###############################################################
#  Generated by:      Cadence Innovus 21.16-s078_1
#  OS:                Linux x86_64(Host ID micro03)
#  Generated on:      Mon Aug  3 20:32:39 2026
#  Design:            oadm_dm
#  Command:           write_lef_abstract oadm_dm.lef -5.7 -PgpinLayers 6 -specifyTopLayer 6 -stripePin
###############################################################

VERSION 5.7 ;

BUSBITCHARS "[]" ;
DIVIDERCHAR "/" ;

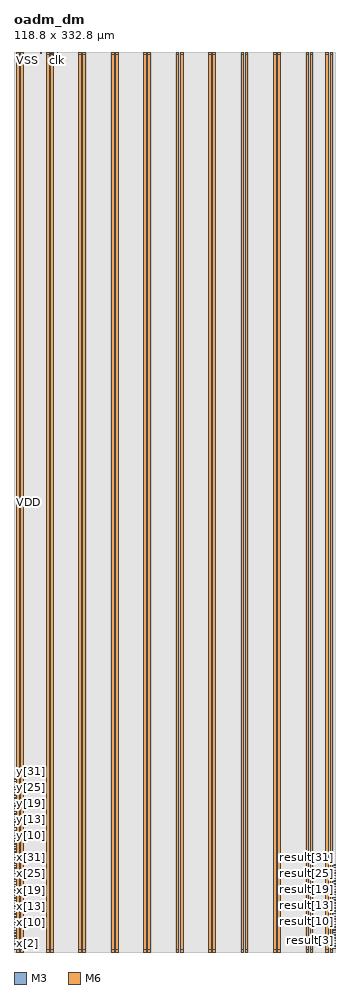
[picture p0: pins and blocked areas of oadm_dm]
MACRO oadm_dm
  CLASS BLOCK ;
  SIZE 118.800000 BY 332.800000 ;
  FOREIGN oadm_dm 0.000000 0.000000 ;
  ORIGIN 0 0 ;
  SYMMETRY X Y R90 ;
  PIN clk
    DIRECTION INPUT ;
    USE SIGNAL ;
    ANTENNAPARTIALMETALAREA 0.03 LAYER M3  ;
    ANTENNAPARTIALMETALSIDEAREA 0.132 LAYER M3  ;
    ANTENNAPARTIALCUTAREA 0.01 LAYER VIA3  ;
    ANTENNAPARTIALMETALAREA 0.898 LAYER M4  ;
    ANTENNAPARTIALMETALSIDEAREA 3.9952 LAYER M4  ;
    ANTENNAPARTIALCUTAREA 0.01 LAYER VIA4  ;
    ANTENNAPARTIALMETALAREA 0.958 LAYER M5  ;
    ANTENNAPARTIALMETALSIDEAREA 4.2592 LAYER M5  ;
    ANTENNAMODEL OXIDE1 ;
    ANTENNAGATEAREA 0.0996 LAYER M5  ;
    ANTENNAMAXAREACAR 11.7269 LAYER M5  ;
    ANTENNAMAXSIDEAREACAR 52.7149 LAYER M5  ;
    ANTENNAMAXCUTCAR 0.401606 LAYER VIA5  ;
    PORT
      LAYER M3 ;
        RECT 15.910000 332.200000 16.090000 332.800000 ;
    END
  END clk
  PIN x[31]
    DIRECTION INPUT ;
    USE SIGNAL ;
    ANTENNAPARTIALMETALAREA 0.579 LAYER M3  ;
    ANTENNAPARTIALMETALSIDEAREA 2.5476 LAYER M3  ;
    ANTENNAMODEL OXIDE1 ;
    ANTENNAGATEAREA 0.0273 LAYER M3  ;
    ANTENNAMAXAREACAR 28.2692 LAYER M3  ;
    ANTENNAMAXSIDEAREACAR 124.821 LAYER M3  ;
    ANTENNAMAXCUTCAR 0.732601 LAYER VIA3  ;
    PORT
      LAYER M3 ;
        RECT 0.000000 31.910000 0.600000 32.090000 ;
    END
  END x[31]
  PIN x[30]
    DIRECTION INPUT ;
    USE SIGNAL ;
    ANTENNAPARTIALMETALAREA 0.709 LAYER M3  ;
    ANTENNAPARTIALMETALSIDEAREA 3.1636 LAYER M3  ;
    ANTENNAMODEL OXIDE1 ;
    ANTENNAGATEAREA 0.0246 LAYER M3  ;
    ANTENNAMAXAREACAR 33.374 LAYER M3  ;
    ANTENNAMAXSIDEAREACAR 147.789 LAYER M3  ;
    ANTENNAMAXCUTCAR 0.813008 LAYER VIA3  ;
    PORT
      LAYER M3 ;
        RECT 0.000000 30.910000 0.600000 31.090000 ;
    END
  END x[30]
  PIN x[29]
    DIRECTION INPUT ;
    USE SIGNAL ;
    ANTENNAPARTIALMETALAREA 0.409 LAYER M3  ;
    ANTENNAPARTIALMETALSIDEAREA 1.8436 LAYER M3  ;
    ANTENNAMODEL OXIDE1 ;
    ANTENNAGATEAREA 0.0246 LAYER M3  ;
    ANTENNAMAXAREACAR 25.2439 LAYER M3  ;
    ANTENNAMAXSIDEAREACAR 112.016 LAYER M3  ;
    ANTENNAMAXCUTCAR 0.813008 LAYER VIA3  ;
    PORT
      LAYER M3 ;
        RECT 0.000000 29.910000 0.600000 30.090000 ;
    END
  END x[29]
  PIN x[28]
    DIRECTION INPUT ;
    USE SIGNAL ;
    ANTENNAPARTIALMETALAREA 0.429 LAYER M3  ;
    ANTENNAPARTIALMETALSIDEAREA 1.9316 LAYER M3  ;
    ANTENNAMODEL OXIDE1 ;
    ANTENNAGATEAREA 0.0246 LAYER M3  ;
    ANTENNAMAXAREACAR 28.4959 LAYER M3  ;
    ANTENNAMAXSIDEAREACAR 126.325 LAYER M3  ;
    ANTENNAMAXCUTCAR 0.813008 LAYER VIA3  ;
    PORT
      LAYER M3 ;
        RECT 0.000000 28.910000 0.600000 29.090000 ;
    END
  END x[28]
  PIN x[27]
    DIRECTION INPUT ;
    USE SIGNAL ;
    ANTENNAPARTIALMETALAREA 0.516 LAYER M3  ;
    ANTENNAPARTIALMETALSIDEAREA 2.3584 LAYER M3  ;
    ANTENNAMODEL OXIDE1 ;
    ANTENNAGATEAREA 0.0246 LAYER M3  ;
    ANTENNAMAXAREACAR 25.2846 LAYER M3  ;
    ANTENNAMAXSIDEAREACAR 113.984 LAYER M3  ;
    ANTENNAMAXCUTCAR 0.813008 LAYER VIA3  ;
    PORT
      LAYER M3 ;
        RECT 0.000000 27.910000 0.600000 28.090000 ;
    END
  END x[27]
  PIN x[26]
    DIRECTION INPUT ;
    USE SIGNAL ;
    ANTENNAPARTIALMETALAREA 0.733 LAYER M3  ;
    ANTENNAPARTIALMETALSIDEAREA 3.2692 LAYER M3  ;
    ANTENNAMODEL OXIDE1 ;
    ANTENNAGATEAREA 0.0546 LAYER M3  ;
    ANTENNAMAXAREACAR 15.2839 LAYER M3  ;
    ANTENNAMAXSIDEAREACAR 68.3663 LAYER M3  ;
    ANTENNAMAXCUTCAR 0.3663 LAYER VIA3  ;
    PORT
      LAYER M3 ;
        RECT 0.000000 26.910000 0.600000 27.090000 ;
    END
  END x[26]
  PIN x[25]
    DIRECTION INPUT ;
    USE SIGNAL ;
    ANTENNAPARTIALMETALAREA 0.169 LAYER M3  ;
    ANTENNAPARTIALMETALSIDEAREA 0.7876 LAYER M3  ;
    ANTENNAMODEL OXIDE1 ;
    ANTENNAGATEAREA 0.0246 LAYER M3  ;
    ANTENNAMAXAREACAR 22.8618 LAYER M3  ;
    ANTENNAMAXSIDEAREACAR 97.7886 LAYER M3  ;
    ANTENNAMAXCUTCAR 0.813008 LAYER VIA3  ;
    PORT
      LAYER M3 ;
        RECT 0.000000 25.910000 0.600000 26.090000 ;
    END
  END x[25]
  PIN x[24]
    DIRECTION INPUT ;
    USE SIGNAL ;
    ANTENNAPARTIALMETALAREA 0.509 LAYER M3  ;
    ANTENNAPARTIALMETALSIDEAREA 2.2836 LAYER M3  ;
    ANTENNAMODEL OXIDE1 ;
    ANTENNAGATEAREA 0.0246 LAYER M3  ;
    ANTENNAMAXAREACAR 25 LAYER M3  ;
    ANTENNAMAXSIDEAREACAR 110.943 LAYER M3  ;
    ANTENNAMAXCUTCAR 0.813008 LAYER VIA3  ;
    PORT
      LAYER M3 ;
        RECT 0.000000 24.910000 0.600000 25.090000 ;
    END
  END x[24]
  PIN x[23]
    DIRECTION INPUT ;
    USE SIGNAL ;
    ANTENNAPARTIALMETALAREA 0.62 LAYER M3  ;
    ANTENNAPARTIALMETALSIDEAREA 2.728 LAYER M3  ;
    ANTENNAPARTIALCUTAREA 0.01 LAYER VIA3  ;
    ANTENNAPARTIALMETALAREA 0.138 LAYER M4  ;
    ANTENNAPARTIALMETALSIDEAREA 0.6512 LAYER M4  ;
    ANTENNAMODEL OXIDE1 ;
    ANTENNAGATEAREA 0.0546 LAYER M4  ;
    ANTENNAMAXAREACAR 6.68498 LAYER M4  ;
    ANTENNAMAXSIDEAREACAR 30.4689 LAYER M4  ;
    ANTENNAMAXCUTCAR 0.549451 LAYER VIA4  ;
    PORT
      LAYER M3 ;
        RECT 0.000000 23.910000 0.600000 24.090000 ;
    END
  END x[23]
  PIN x[22]
    DIRECTION INPUT ;
    USE SIGNAL ;
    ANTENNAPARTIALMETALAREA 0.633 LAYER M3  ;
    ANTENNAPARTIALMETALSIDEAREA 2.8292 LAYER M3  ;
    ANTENNAMODEL OXIDE1 ;
    ANTENNAGATEAREA 0.1092 LAYER M3  ;
    ANTENNAMAXAREACAR 6.81181 LAYER M3  ;
    ANTENNAMAXSIDEAREACAR 30.533 LAYER M3  ;
    ANTENNAMAXCUTCAR 0.18315 LAYER VIA3  ;
    PORT
      LAYER M3 ;
        RECT 0.000000 22.910000 0.600000 23.090000 ;
    END
  END x[22]
  PIN x[21]
    DIRECTION INPUT ;
    USE SIGNAL ;
    ANTENNAPARTIALMETALAREA 0.869 LAYER M3  ;
    ANTENNAPARTIALMETALSIDEAREA 3.8676 LAYER M3  ;
    ANTENNAMODEL OXIDE1 ;
    ANTENNAGATEAREA 0.0498 LAYER M3  ;
    ANTENNAMAXAREACAR 20.1807 LAYER M3  ;
    ANTENNAMAXSIDEAREACAR 89.261 LAYER M3  ;
    ANTENNAMAXCUTCAR 0.401606 LAYER VIA3  ;
    PORT
      LAYER M3 ;
        RECT 0.000000 21.910000 0.600000 22.090000 ;
    END
  END x[21]
  PIN x[20]
    DIRECTION INPUT ;
    USE SIGNAL ;
    ANTENNAPARTIALMETALAREA 0.415 LAYER M3  ;
    ANTENNAPARTIALMETALSIDEAREA 1.826 LAYER M3  ;
    ANTENNAMODEL OXIDE1 ;
    ANTENNAGATEAREA 0.0246 LAYER M3  ;
    ANTENNAMAXAREACAR 21.1789 LAYER M3  ;
    ANTENNAMAXSIDEAREACAR 92.3415 LAYER M3  ;
    ANTENNAMAXCUTCAR 0.813008 LAYER VIA3  ;
    PORT
      LAYER M3 ;
        RECT 0.000000 20.910000 0.600000 21.090000 ;
    END
  END x[20]
  PIN x[19]
    DIRECTION INPUT ;
    USE SIGNAL ;
    ANTENNAPARTIALMETALAREA 0.599 LAYER M3  ;
    ANTENNAPARTIALMETALSIDEAREA 2.6356 LAYER M3  ;
    ANTENNAMODEL OXIDE1 ;
    ANTENNAGATEAREA 0.0273 LAYER M3  ;
    ANTENNAMAXAREACAR 25.4908 LAYER M3  ;
    ANTENNAMAXSIDEAREACAR 113.26 LAYER M3  ;
    ANTENNAMAXCUTCAR 0.732601 LAYER VIA3  ;
    PORT
      LAYER M3 ;
        RECT 0.000000 19.910000 0.600000 20.090000 ;
    END
  END x[19]
  PIN x[18]
    DIRECTION INPUT ;
    USE SIGNAL ;
    ANTENNAPARTIALMETALAREA 0.669 LAYER M3  ;
    ANTENNAPARTIALMETALSIDEAREA 2.9876 LAYER M3  ;
    ANTENNAMODEL OXIDE1 ;
    ANTENNAGATEAREA 0.0246 LAYER M3  ;
    ANTENNAMAXAREACAR 35.813 LAYER M3  ;
    ANTENNAMAXSIDEAREACAR 158.52 LAYER M3  ;
    ANTENNAMAXCUTCAR 0.813008 LAYER VIA3  ;
    PORT
      LAYER M3 ;
        RECT 0.000000 18.910000 0.600000 19.090000 ;
    END
  END x[18]
  PIN x[17]
    DIRECTION INPUT ;
    USE SIGNAL ;
    ANTENNAPARTIALMETALAREA 0.399 LAYER M3  ;
    ANTENNAPARTIALMETALSIDEAREA 1.7556 LAYER M3  ;
    ANTENNAMODEL OXIDE1 ;
    ANTENNAGATEAREA 0.0246 LAYER M3  ;
    ANTENNAMAXAREACAR 26.4634 LAYER M3  ;
    ANTENNAMAXSIDEAREACAR 115.593 LAYER M3  ;
    ANTENNAMAXCUTCAR 0.813008 LAYER VIA3  ;
    PORT
      LAYER M3 ;
        RECT 0.000000 17.910000 0.600000 18.090000 ;
    END
  END x[17]
  PIN x[16]
    DIRECTION INPUT ;
    USE SIGNAL ;
    ANTENNAPARTIALCUTAREA 0.01 LAYER VIA3  ;
    ANTENNAPARTIALMETALAREA 0.158 LAYER M4  ;
    ANTENNAPARTIALMETALSIDEAREA 0.7392 LAYER M4  ;
    ANTENNAMODEL OXIDE1 ;
    ANTENNAGATEAREA 0.0546 LAYER M4  ;
    ANTENNAMAXAREACAR 21.3828 LAYER M4  ;
    ANTENNAMAXSIDEAREACAR 96.0073 LAYER M4  ;
    ANTENNAMAXCUTCAR 0.549451 LAYER VIA4  ;
    PORT
      LAYER M3 ;
        RECT 0.000000 16.910000 0.600000 17.090000 ;
    END
  END x[16]
  PIN x[15]
    DIRECTION INPUT ;
    USE SIGNAL ;
    ANTENNAPARTIALMETALAREA 1.007 LAYER M3  ;
    ANTENNAPARTIALMETALSIDEAREA 4.5188 LAYER M3  ;
    ANTENNAMODEL OXIDE1 ;
    ANTENNAGATEAREA 0.0546 LAYER M3  ;
    ANTENNAMAXAREACAR 21.1447 LAYER M3  ;
    ANTENNAMAXSIDEAREACAR 94.9597 LAYER M3  ;
    ANTENNAMAXCUTCAR 0.3663 LAYER VIA3  ;
    PORT
      LAYER M3 ;
        RECT 0.000000 15.910000 0.600000 16.090000 ;
    END
  END x[15]
  PIN x[14]
    DIRECTION INPUT ;
    USE SIGNAL ;
    ANTENNAPARTIALMETALAREA 0.419 LAYER M3  ;
    ANTENNAPARTIALMETALSIDEAREA 1.8436 LAYER M3  ;
    ANTENNAMODEL OXIDE1 ;
    ANTENNAGATEAREA 0.0246 LAYER M3  ;
    ANTENNAMAXAREACAR 22.3984 LAYER M3  ;
    ANTENNAMAXSIDEAREACAR 97.7073 LAYER M3  ;
    ANTENNAMAXCUTCAR 0.813008 LAYER VIA3  ;
    PORT
      LAYER M3 ;
        RECT 0.000000 14.910000 0.600000 15.090000 ;
    END
  END x[14]
  PIN x[13]
    DIRECTION INPUT ;
    USE SIGNAL ;
    ANTENNAPARTIALMETALAREA 0.896 LAYER M3  ;
    ANTENNAPARTIALMETALSIDEAREA 4.0304 LAYER M3  ;
    ANTENNAMODEL OXIDE1 ;
    ANTENNAGATEAREA 0.0546 LAYER M3  ;
    ANTENNAMAXAREACAR 18.4908 LAYER M3  ;
    ANTENNAMAXSIDEAREACAR 82.6374 LAYER M3  ;
    ANTENNAMAXCUTCAR 0.3663 LAYER VIA3  ;
    PORT
      LAYER M3 ;
        RECT 0.000000 13.910000 0.600000 14.090000 ;
    END
  END x[13]
  PIN x[12]
    DIRECTION INPUT ;
    USE SIGNAL ;
    ANTENNAPARTIALMETALAREA 0.747 LAYER M3  ;
    ANTENNAPARTIALMETALSIDEAREA 3.3748 LAYER M3  ;
    ANTENNAMODEL OXIDE1 ;
    ANTENNAGATEAREA 0.0546 LAYER M3  ;
    ANTENNAMAXAREACAR 16.2381 LAYER M3  ;
    ANTENNAMAXSIDEAREACAR 72.7253 LAYER M3  ;
    ANTENNAMAXCUTCAR 0.3663 LAYER VIA3  ;
    PORT
      LAYER M3 ;
        RECT 0.000000 12.910000 0.600000 13.090000 ;
    END
  END x[12]
  PIN x[11]
    DIRECTION INPUT ;
    USE SIGNAL ;
    ANTENNAPARTIALMETALAREA 0.529 LAYER M3  ;
    ANTENNAPARTIALMETALSIDEAREA 2.3716 LAYER M3  ;
    ANTENNAMODEL OXIDE1 ;
    ANTENNAGATEAREA 0.0273 LAYER M3  ;
    ANTENNAMAXAREACAR 23.1465 LAYER M3  ;
    ANTENNAMAXSIDEAREACAR 104.557 LAYER M3  ;
    ANTENNAMAXCUTCAR 0.732601 LAYER VIA3  ;
    PORT
      LAYER M3 ;
        RECT 0.000000 11.910000 0.600000 12.090000 ;
    END
  END x[11]
  PIN x[10]
    DIRECTION INPUT ;
    USE SIGNAL ;
    ANTENNAPARTIALMETALAREA 0.659 LAYER M3  ;
    ANTENNAPARTIALMETALSIDEAREA 2.8996 LAYER M3  ;
    ANTENNAMODEL OXIDE1 ;
    ANTENNAGATEAREA 0.0546 LAYER M3  ;
    ANTENNAMAXAREACAR 23.0513 LAYER M3  ;
    ANTENNAMAXSIDEAREACAR 101.092 LAYER M3  ;
    ANTENNAMAXCUTCAR 0.3663 LAYER VIA3  ;
    PORT
      LAYER M3 ;
        RECT 0.000000 10.910000 0.600000 11.090000 ;
    END
  END x[10]
  PIN x[9]
    DIRECTION INPUT ;
    USE SIGNAL ;
    ANTENNAPARTIALMETALAREA 0.749 LAYER M3  ;
    ANTENNAPARTIALMETALSIDEAREA 3.3396 LAYER M3  ;
    ANTENNAMODEL OXIDE1 ;
    ANTENNAGATEAREA 0.0546 LAYER M3  ;
    ANTENNAMAXAREACAR 22.1355 LAYER M3  ;
    ANTENNAMAXSIDEAREACAR 97.8681 LAYER M3  ;
    ANTENNAMAXCUTCAR 0.3663 LAYER VIA3  ;
    PORT
      LAYER M3 ;
        RECT 0.000000 9.910000 0.600000 10.090000 ;
    END
  END x[9]
  PIN x[8]
    DIRECTION INPUT ;
    USE SIGNAL ;
    ANTENNAPARTIALMETALAREA 0.018 LAYER M3  ;
    ANTENNAPARTIALMETALSIDEAREA 0.1232 LAYER M3  ;
    ANTENNAMODEL OXIDE1 ;
    ANTENNAGATEAREA 0.0546 LAYER M3  ;
    ANTENNAMAXAREACAR 14.707 LAYER M3  ;
    ANTENNAMAXSIDEAREACAR 62.4396 LAYER M3  ;
    ANTENNAMAXCUTCAR 0.3663 LAYER VIA3  ;
    PORT
      LAYER M3 ;
        RECT 0.000000 8.910000 0.600000 9.090000 ;
    END
  END x[8]
  PIN x[7]
    DIRECTION INPUT ;
    USE SIGNAL ;
    ANTENNAPARTIALMETALAREA 0.587 LAYER M3  ;
    ANTENNAPARTIALMETALSIDEAREA 2.6708 LAYER M3  ;
    ANTENNAMODEL OXIDE1 ;
    ANTENNAGATEAREA 0.1092 LAYER M3  ;
    ANTENNAMAXAREACAR 6.39057 LAYER M3  ;
    ANTENNAMAXSIDEAREACAR 29.0824 LAYER M3  ;
    ANTENNAMAXCUTCAR 0.18315 LAYER VIA3  ;
    PORT
      LAYER M3 ;
        RECT 0.000000 7.910000 0.600000 8.090000 ;
    END
  END x[7]
  PIN x[6]
    DIRECTION INPUT ;
    USE SIGNAL ;
    ANTENNAPARTIALMETALAREA 0.489 LAYER M3  ;
    ANTENNAPARTIALMETALSIDEAREA 2.1956 LAYER M3  ;
    ANTENNAMODEL OXIDE1 ;
    ANTENNAGATEAREA 0.1092 LAYER M3  ;
    ANTENNAMAXAREACAR 13.6067 LAYER M3  ;
    ANTENNAMAXSIDEAREACAR 60.4304 LAYER M3  ;
    ANTENNAMAXCUTCAR 0.18315 LAYER VIA3  ;
    PORT
      LAYER M3 ;
        RECT 0.000000 6.910000 0.600000 7.090000 ;
    END
  END x[6]
  PIN x[5]
    DIRECTION INPUT ;
    USE SIGNAL ;
    ANTENNAPARTIALMETALAREA 0.256 LAYER M3  ;
    ANTENNAPARTIALMETALSIDEAREA 1.2144 LAYER M3  ;
    ANTENNAMODEL OXIDE1 ;
    ANTENNAGATEAREA 0.1092 LAYER M3  ;
    ANTENNAMAXAREACAR 3.35943 LAYER M3  ;
    ANTENNAMAXSIDEAREACAR 15.7454 LAYER M3  ;
    ANTENNAMAXCUTCAR 0.18315 LAYER VIA3  ;
    PORT
      LAYER M3 ;
        RECT 0.000000 5.910000 0.600000 6.090000 ;
    END
  END x[5]
  PIN x[4]
    DIRECTION INPUT ;
    USE SIGNAL ;
    ANTENNAPARTIALMETALAREA 0.449 LAYER M3  ;
    ANTENNAPARTIALMETALSIDEAREA 2.0196 LAYER M3  ;
    ANTENNAMODEL OXIDE1 ;
    ANTENNAGATEAREA 0.1092 LAYER M3  ;
    ANTENNAMAXAREACAR 6.83013 LAYER M3  ;
    ANTENNAMAXSIDEAREACAR 30.6136 LAYER M3  ;
    ANTENNAMAXCUTCAR 0.18315 LAYER VIA3  ;
    PORT
      LAYER M3 ;
        RECT 0.000000 4.910000 0.600000 5.090000 ;
    END
  END x[4]
  PIN x[3]
    DIRECTION INPUT ;
    USE SIGNAL ;
    ANTENNAPARTIALMETALAREA 0.687 LAYER M3  ;
    ANTENNAPARTIALMETALSIDEAREA 3.1108 LAYER M3  ;
    ANTENNAMODEL OXIDE1 ;
    ANTENNAGATEAREA 0.1092 LAYER M3  ;
    ANTENNAMAXAREACAR 7.54441 LAYER M3  ;
    ANTENNAMAXSIDEAREACAR 34.1593 LAYER M3  ;
    ANTENNAMAXCUTCAR 0.18315 LAYER VIA3  ;
    PORT
      LAYER M3 ;
        RECT 0.000000 3.910000 0.600000 4.090000 ;
    END
  END x[3]
  PIN x[2]
    DIRECTION INPUT ;
    USE SIGNAL ;
    ANTENNAPARTIALMETALAREA 0.967 LAYER M3  ;
    ANTENNAPARTIALMETALSIDEAREA 4.3428 LAYER M3  ;
    ANTENNAMODEL OXIDE1 ;
    ANTENNAGATEAREA 0.1092 LAYER M3  ;
    ANTENNAMAXAREACAR 9.87042 LAYER M3  ;
    ANTENNAMAXSIDEAREACAR 44.3938 LAYER M3  ;
    ANTENNAMAXCUTCAR 0.18315 LAYER VIA3  ;
    PORT
      LAYER M3 ;
        RECT 0.000000 2.910000 0.600000 3.090000 ;
    END
  END x[2]
  PIN x[1]
    DIRECTION INPUT ;
    USE SIGNAL ;
    ANTENNAPARTIALMETALAREA 0.689 LAYER M3  ;
    ANTENNAPARTIALMETALSIDEAREA 3.0756 LAYER M3  ;
    ANTENNAMODEL OXIDE1 ;
    ANTENNAGATEAREA 0.0498 LAYER M3  ;
    ANTENNAMAXAREACAR 22.1084 LAYER M3  ;
    ANTENNAMAXSIDEAREACAR 97.743 LAYER M3  ;
    ANTENNAMAXCUTCAR 0.401606 LAYER VIA3  ;
    PORT
      LAYER M3 ;
        RECT 0.000000 1.910000 0.600000 2.090000 ;
    END
  END x[1]
  PIN x[0]
    DIRECTION INPUT ;
    USE SIGNAL ;
    ANTENNAPARTIALMETALAREA 0.529 LAYER M3  ;
    ANTENNAPARTIALMETALSIDEAREA 2.3716 LAYER M3  ;
    ANTENNAMODEL OXIDE1 ;
    ANTENNAGATEAREA 0.0498 LAYER M3  ;
    ANTENNAMAXAREACAR 20.9036 LAYER M3  ;
    ANTENNAMAXSIDEAREACAR 92.4418 LAYER M3  ;
    ANTENNAMAXCUTCAR 0.401606 LAYER VIA3  ;
    PORT
      LAYER M3 ;
        RECT 0.000000 0.910000 0.600000 1.090000 ;
    END
  END x[0]
  PIN y[31]
    DIRECTION INPUT ;
    USE SIGNAL ;
    ANTENNAPARTIALMETALAREA 0.509 LAYER M3  ;
    ANTENNAPARTIALMETALSIDEAREA 2.2836 LAYER M3  ;
    ANTENNAMODEL OXIDE1 ;
    ANTENNAGATEAREA 0.0246 LAYER M3  ;
    ANTENNAMAXAREACAR 29.3089 LAYER M3  ;
    ANTENNAMAXSIDEAREACAR 129.902 LAYER M3  ;
    ANTENNAMAXCUTCAR 0.813008 LAYER VIA3  ;
    PORT
      LAYER M3 ;
        RECT 0.000000 63.910000 0.600000 64.090000 ;
    END
  END y[31]
  PIN y[30]
    DIRECTION INPUT ;
    USE SIGNAL ;
    ANTENNAPARTIALMETALAREA 0.847 LAYER M3  ;
    ANTENNAPARTIALMETALSIDEAREA 3.8148 LAYER M3  ;
    ANTENNAMODEL OXIDE1 ;
    ANTENNAGATEAREA 0.0246 LAYER M3  ;
    ANTENNAMAXAREACAR 47.1138 LAYER M3  ;
    ANTENNAMAXSIDEAREACAR 210.033 LAYER M3  ;
    ANTENNAMAXCUTCAR 0.813008 LAYER VIA3  ;
    PORT
      LAYER M3 ;
        RECT 0.000000 62.910000 0.600000 63.090000 ;
    END
  END y[30]
  PIN y[29]
    DIRECTION INPUT ;
    USE SIGNAL ;
    ANTENNAPARTIALMETALAREA 0.018 LAYER M3  ;
    ANTENNAPARTIALMETALSIDEAREA 0.1232 LAYER M3  ;
    ANTENNAMODEL OXIDE1 ;
    ANTENNAGATEAREA 0.0246 LAYER M3  ;
    ANTENNAMAXAREACAR 37.9431 LAYER M3  ;
    ANTENNAMAXSIDEAREACAR 161.512 LAYER M3  ;
    ANTENNAMAXCUTCAR 0.813008 LAYER VIA3  ;
    PORT
      LAYER M3 ;
        RECT 0.000000 61.910000 0.600000 62.090000 ;
    END
  END y[29]
  PIN y[28]
    DIRECTION INPUT ;
    USE SIGNAL ;
    ANTENNAPARTIALMETALAREA 0.469 LAYER M3  ;
    ANTENNAPARTIALMETALSIDEAREA 2.1076 LAYER M3  ;
    ANTENNAMODEL OXIDE1 ;
    ANTENNAGATEAREA 0.0246 LAYER M3  ;
    ANTENNAMAXAREACAR 43.9431 LAYER M3  ;
    ANTENNAMAXSIDEAREACAR 194.293 LAYER M3  ;
    ANTENNAMAXCUTCAR 0.813008 LAYER VIA3  ;
    PORT
      LAYER M3 ;
        RECT 0.000000 60.910000 0.600000 61.090000 ;
    END
  END y[28]
  PIN y[27]
    DIRECTION INPUT ;
    USE SIGNAL ;
    ANTENNAPARTIALMETALAREA 0.029 LAYER M3  ;
    ANTENNAPARTIALMETALSIDEAREA 0.1716 LAYER M3  ;
    ANTENNAMODEL OXIDE1 ;
    ANTENNAGATEAREA 0.0246 LAYER M3  ;
    ANTENNAMAXAREACAR 20.6667 LAYER M3  ;
    ANTENNAMAXSIDEAREACAR 86.0813 LAYER M3  ;
    ANTENNAMAXCUTCAR 0.813008 LAYER VIA3  ;
    PORT
      LAYER M3 ;
        RECT 0.000000 59.910000 0.600000 60.090000 ;
    END
  END y[27]
  PIN y[26]
    DIRECTION INPUT ;
    USE SIGNAL ;
    ANTENNAPARTIALMETALAREA 0.749 LAYER M3  ;
    ANTENNAPARTIALMETALSIDEAREA 3.3396 LAYER M3  ;
    ANTENNAMODEL OXIDE1 ;
    ANTENNAGATEAREA 0.0246 LAYER M3  ;
    ANTENNAMAXAREACAR 54.5122 LAYER M3  ;
    ANTENNAMAXSIDEAREACAR 240.797 LAYER M3  ;
    ANTENNAMAXCUTCAR 0.813008 LAYER VIA3  ;
    PORT
      LAYER M3 ;
        RECT 0.000000 58.910000 0.600000 59.090000 ;
    END
  END y[26]
  PIN y[25]
    DIRECTION INPUT ;
    USE SIGNAL ;
    ANTENNAPARTIALMETALAREA 0.589 LAYER M3  ;
    ANTENNAPARTIALMETALSIDEAREA 2.6356 LAYER M3  ;
    ANTENNAMODEL OXIDE1 ;
    ANTENNAGATEAREA 0.0246 LAYER M3  ;
    ANTENNAMAXAREACAR 59.3902 LAYER M3  ;
    ANTENNAMAXSIDEAREACAR 262.26 LAYER M3  ;
    ANTENNAMAXCUTCAR 0.813008 LAYER VIA3  ;
    PORT
      LAYER M3 ;
        RECT 0.000000 57.910000 0.600000 58.090000 ;
    END
  END y[25]
  PIN y[24]
    DIRECTION INPUT ;
    USE SIGNAL ;
    ANTENNAPARTIALMETALAREA 0.547 LAYER M3  ;
    ANTENNAPARTIALMETALSIDEAREA 2.4948 LAYER M3  ;
    ANTENNAMODEL OXIDE1 ;
    ANTENNAGATEAREA 0.0246 LAYER M3  ;
    ANTENNAMAXAREACAR 29.2276 LAYER M3  ;
    ANTENNAMAXSIDEAREACAR 131.333 LAYER M3  ;
    ANTENNAMAXCUTCAR 0.813008 LAYER VIA3  ;
    PORT
      LAYER M3 ;
        RECT 0.000000 56.910000 0.600000 57.090000 ;
    END
  END y[24]
  PIN y[23]
    DIRECTION INPUT ;
    USE SIGNAL ;
    ANTENNAPARTIALMETALAREA 0.649 LAYER M3  ;
    ANTENNAPARTIALMETALSIDEAREA 2.8996 LAYER M3  ;
    ANTENNAMODEL OXIDE1 ;
    ANTENNAGATEAREA 0.0546 LAYER M3  ;
    ANTENNAMAXAREACAR 13.7454 LAYER M3  ;
    ANTENNAMAXSIDEAREACAR 61.5971 LAYER M3  ;
    ANTENNAMAXCUTCAR 0.3663 LAYER VIA3  ;
    PORT
      LAYER M3 ;
        RECT 0.000000 55.910000 0.600000 56.090000 ;
    END
  END y[23]
  PIN y[22]
    DIRECTION INPUT ;
    USE SIGNAL ;
    ANTENNAPARTIALMETALAREA 0.619 LAYER M3  ;
    ANTENNAPARTIALMETALSIDEAREA 2.7236 LAYER M3  ;
    ANTENNAPARTIALCUTAREA 0.01 LAYER VIA3  ;
    ANTENNAPARTIALMETALAREA 0.258 LAYER M4  ;
    ANTENNAPARTIALMETALSIDEAREA 1.1792 LAYER M4  ;
    ANTENNAMODEL OXIDE1 ;
    ANTENNAGATEAREA 0.1092 LAYER M4  ;
    ANTENNAMAXAREACAR 3.85394 LAYER M4  ;
    ANTENNAMAXSIDEAREACAR 17.9212 LAYER M4  ;
    ANTENNAMAXCUTCAR 0.274725 LAYER VIA4  ;
    PORT
      LAYER M3 ;
        RECT 0.000000 54.910000 0.600000 55.090000 ;
    END
  END y[22]
  PIN y[21]
    DIRECTION INPUT ;
    USE SIGNAL ;
    ANTENNAPARTIALMETALAREA 0.449 LAYER M3  ;
    ANTENNAPARTIALMETALSIDEAREA 2.0196 LAYER M3  ;
    ANTENNAMODEL OXIDE1 ;
    ANTENNAGATEAREA 0.0498 LAYER M3  ;
    ANTENNAMAXAREACAR 14.0763 LAYER M3  ;
    ANTENNAMAXSIDEAREACAR 62.4016 LAYER M3  ;
    ANTENNAMAXCUTCAR 0.401606 LAYER VIA3  ;
    PORT
      LAYER M3 ;
        RECT 0.000000 53.910000 0.600000 54.090000 ;
    END
  END y[21]
  PIN y[20]
    DIRECTION INPUT ;
    USE SIGNAL ;
    ANTENNAPARTIALMETALAREA 0.307 LAYER M3  ;
    ANTENNAPARTIALMETALSIDEAREA 1.4388 LAYER M3  ;
    ANTENNAMODEL OXIDE1 ;
    ANTENNAGATEAREA 0.0546 LAYER M3  ;
    ANTENNAMAXAREACAR 9.42308 LAYER M3  ;
    ANTENNAMAXSIDEAREACAR 43.3846 LAYER M3  ;
    ANTENNAMAXCUTCAR 0.3663 LAYER VIA3  ;
    PORT
      LAYER M3 ;
        RECT 0.000000 52.910000 0.600000 53.090000 ;
    END
  END y[20]
  PIN y[19]
    DIRECTION INPUT ;
    USE SIGNAL ;
    ANTENNAPARTIALMETALAREA 0.689 LAYER M3  ;
    ANTENNAPARTIALMETALSIDEAREA 3.0756 LAYER M3  ;
    ANTENNAMODEL OXIDE1 ;
    ANTENNAGATEAREA 0.0546 LAYER M3  ;
    ANTENNAMAXAREACAR 14.6996 LAYER M3  ;
    ANTENNAMAXSIDEAREACAR 65.1502 LAYER M3  ;
    ANTENNAMAXCUTCAR 0.3663 LAYER VIA3  ;
    PORT
      LAYER M3 ;
        RECT 0.000000 51.910000 0.600000 52.090000 ;
    END
  END y[19]
  PIN y[18]
    DIRECTION INPUT ;
    USE SIGNAL ;
    ANTENNAPARTIALMETALAREA 0.809 LAYER M3  ;
    ANTENNAPARTIALMETALSIDEAREA 3.6036 LAYER M3  ;
    ANTENNAMODEL OXIDE1 ;
    ANTENNAGATEAREA 0.0546 LAYER M3  ;
    ANTENNAMAXAREACAR 17.0073 LAYER M3  ;
    ANTENNAMAXSIDEAREACAR 75.304 LAYER M3  ;
    ANTENNAMAXCUTCAR 0.3663 LAYER VIA3  ;
    PORT
      LAYER M3 ;
        RECT 0.000000 50.910000 0.600000 51.090000 ;
    END
  END y[18]
  PIN y[17]
    DIRECTION INPUT ;
    USE SIGNAL ;
    ANTENNAMODEL OXIDE1 ;
    ANTENNAGATEAREA 0.0546 LAYER M3  ;
    ANTENNAMAXAREACAR 8.77289 LAYER M3  ;
    ANTENNAMAXSIDEAREACAR 35.5238 LAYER M3  ;
    ANTENNAMAXCUTCAR 0.3663 LAYER VIA3  ;
    PORT
      LAYER M3 ;
        RECT 0.000000 49.910000 0.600000 50.090000 ;
    END
  END y[17]
  PIN y[16]
    DIRECTION INPUT ;
    USE SIGNAL ;
    ANTENNAPARTIALMETALAREA 0.018 LAYER M3  ;
    ANTENNAPARTIALMETALSIDEAREA 0.1232 LAYER M3  ;
    ANTENNAMODEL OXIDE1 ;
    ANTENNAGATEAREA 0.0546 LAYER M3  ;
    ANTENNAMAXAREACAR 9.21245 LAYER M3  ;
    ANTENNAMAXSIDEAREACAR 38.2637 LAYER M3  ;
    ANTENNAMAXCUTCAR 0.3663 LAYER VIA3  ;
    PORT
      LAYER M3 ;
        RECT 0.000000 48.910000 0.600000 49.090000 ;
    END
  END y[16]
  PIN y[15]
    DIRECTION INPUT ;
    USE SIGNAL ;
    ANTENNAPARTIALMETALAREA 0.489 LAYER M3  ;
    ANTENNAPARTIALMETALSIDEAREA 2.1956 LAYER M3  ;
    ANTENNAMODEL OXIDE1 ;
    ANTENNAGATEAREA 0.0546 LAYER M3  ;
    ANTENNAMAXAREACAR 10.9038 LAYER M3  ;
    ANTENNAMAXSIDEAREACAR 49.1538 LAYER M3  ;
    ANTENNAMAXCUTCAR 0.3663 LAYER VIA3  ;
    PORT
      LAYER M3 ;
        RECT 0.000000 47.910000 0.600000 48.090000 ;
    END
  END y[15]
  PIN y[14]
    DIRECTION INPUT ;
    USE SIGNAL ;
    ANTENNAPARTIALMETALAREA 0.489 LAYER M3  ;
    ANTENNAPARTIALMETALSIDEAREA 2.1956 LAYER M3  ;
    ANTENNAMODEL OXIDE1 ;
    ANTENNAGATEAREA 0.0246 LAYER M3  ;
    ANTENNAMAXAREACAR 24.4309 LAYER M3  ;
    ANTENNAMAXSIDEAREACAR 108.439 LAYER M3  ;
    ANTENNAMAXCUTCAR 0.813008 LAYER VIA3  ;
    PORT
      LAYER M3 ;
        RECT 0.000000 46.910000 0.600000 47.090000 ;
    END
  END y[14]
  PIN y[13]
    DIRECTION INPUT ;
    USE SIGNAL ;
    ANTENNAPARTIALMETALAREA 0.019 LAYER M3  ;
    ANTENNAPARTIALMETALSIDEAREA 0.0836 LAYER M3  ;
    ANTENNAMODEL OXIDE1 ;
    ANTENNAGATEAREA 0.0498 LAYER M3  ;
    ANTENNAMAXAREACAR 10.008 LAYER M3  ;
    ANTENNAMAXSIDEAREACAR 40.755 LAYER M3  ;
    ANTENNAMAXCUTCAR 0.401606 LAYER VIA3  ;
    PORT
      LAYER M3 ;
        RECT 0.000000 45.910000 0.600000 46.090000 ;
    END
  END y[13]
  PIN y[12]
    DIRECTION INPUT ;
    USE SIGNAL ;
    ANTENNAPARTIALMETALAREA 0.78 LAYER M3  ;
    ANTENNAPARTIALMETALSIDEAREA 3.432 LAYER M3  ;
    ANTENNAMODEL OXIDE1 ;
    ANTENNAGATEAREA 0.0498 LAYER M3  ;
    ANTENNAMAXAREACAR 17.9116 LAYER M3  ;
    ANTENNAMAXSIDEAREACAR 78.3936 LAYER M3  ;
    ANTENNAMAXCUTCAR 0.401606 LAYER VIA3  ;
    PORT
      LAYER M3 ;
        RECT 0.000000 44.910000 0.600000 45.090000 ;
    END
  END y[12]
  PIN y[11]
    DIRECTION INPUT ;
    USE SIGNAL ;
    ANTENNAMODEL OXIDE1 ;
    ANTENNAGATEAREA 0.0498 LAYER M3  ;
    ANTENNAMAXAREACAR 10.7912 LAYER M3  ;
    ANTENNAMAXSIDEAREACAR 44.0562 LAYER M3  ;
    ANTENNAMAXCUTCAR 0.401606 LAYER VIA3  ;
    PORT
      LAYER M3 ;
        RECT 0.000000 43.910000 0.600000 44.090000 ;
    END
  END y[11]
  PIN y[10]
    DIRECTION INPUT ;
    USE SIGNAL ;
    ANTENNAPARTIALMETALAREA 0.569 LAYER M3  ;
    ANTENNAPARTIALMETALSIDEAREA 2.5476 LAYER M3  ;
    ANTENNAMODEL OXIDE1 ;
    ANTENNAGATEAREA 0.1092 LAYER M3  ;
    ANTENNAMAXAREACAR 6.22573 LAYER M3  ;
    ANTENNAMAXSIDEAREACAR 27.9542 LAYER M3  ;
    ANTENNAMAXCUTCAR 0.18315 LAYER VIA3  ;
    PORT
      LAYER M3 ;
        RECT 0.000000 42.910000 0.600000 43.090000 ;
    END
  END y[10]
  PIN y[9]
    DIRECTION INPUT ;
    USE SIGNAL ;
    ANTENNAPARTIALMETALAREA 0.409 LAYER M3  ;
    ANTENNAPARTIALMETALSIDEAREA 1.8436 LAYER M3  ;
    ANTENNAMODEL OXIDE1 ;
    ANTENNAGATEAREA 0.0273 LAYER M3  ;
    ANTENNAMAXAREACAR 23.9304 LAYER M3  ;
    ANTENNAMAXSIDEAREACAR 107.267 LAYER M3  ;
    ANTENNAMAXCUTCAR 0.732601 LAYER VIA3  ;
    PORT
      LAYER M3 ;
        RECT 0.000000 41.910000 0.600000 42.090000 ;
    END
  END y[9]
  PIN y[8]
    DIRECTION INPUT ;
    USE SIGNAL ;
    ANTENNAPARTIALMETALAREA 0.399 LAYER M3  ;
    ANTENNAPARTIALMETALSIDEAREA 1.7556 LAYER M3  ;
    ANTENNAMODEL OXIDE1 ;
    ANTENNAGATEAREA 0.1092 LAYER M3  ;
    ANTENNAMAXAREACAR 4.85119 LAYER M3  ;
    ANTENNAMAXSIDEAREACAR 21.3938 LAYER M3  ;
    ANTENNAMAXCUTCAR 0.18315 LAYER VIA3  ;
    PORT
      LAYER M3 ;
        RECT 0.000000 40.910000 0.600000 41.090000 ;
    END
  END y[8]
  PIN y[7]
    DIRECTION INPUT ;
    USE SIGNAL ;
    ANTENNAPARTIALMETALAREA 0.729 LAYER M3  ;
    ANTENNAPARTIALMETALSIDEAREA 3.2516 LAYER M3  ;
    ANTENNAMODEL OXIDE1 ;
    ANTENNAGATEAREA 0.1092 LAYER M3  ;
    ANTENNAMAXAREACAR 8.47756 LAYER M3  ;
    ANTENNAMAXSIDEAREACAR 37.7527 LAYER M3  ;
    ANTENNAMAXCUTCAR 0.18315 LAYER VIA3  ;
    PORT
      LAYER M3 ;
        RECT 0.000000 39.910000 0.600000 40.090000 ;
    END
  END y[7]
  PIN y[6]
    DIRECTION INPUT ;
    USE SIGNAL ;
    ANTENNAPARTIALMETALAREA 0.429 LAYER M3  ;
    ANTENNAPARTIALMETALSIDEAREA 1.9316 LAYER M3  ;
    ANTENNAMODEL OXIDE1 ;
    ANTENNAGATEAREA 0.0996 LAYER M3  ;
    ANTENNAMAXAREACAR 5.43173 LAYER M3  ;
    ANTENNAMAXSIDEAREACAR 24.1325 LAYER M3  ;
    ANTENNAMAXCUTCAR 0.200803 LAYER VIA3  ;
    PORT
      LAYER M3 ;
        RECT 0.000000 38.910000 0.600000 39.090000 ;
    END
  END y[6]
  PIN y[5]
    DIRECTION INPUT ;
    USE SIGNAL ;
    ANTENNAPARTIALMETALAREA 0.572 LAYER M3  ;
    ANTENNAPARTIALMETALSIDEAREA 2.5608 LAYER M3  ;
    ANTENNAMODEL OXIDE1 ;
    ANTENNAGATEAREA 0.0273 LAYER M3  ;
    ANTENNAMAXAREACAR 24.978 LAYER M3  ;
    ANTENNAMAXSIDEAREACAR 112.615 LAYER M3  ;
    ANTENNAMAXCUTCAR 0.732601 LAYER VIA3  ;
    PORT
      LAYER M3 ;
        RECT 0.000000 37.910000 0.600000 38.090000 ;
    END
  END y[5]
  PIN y[4]
    DIRECTION INPUT ;
    USE SIGNAL ;
    ANTENNAPARTIALMETALAREA 0.018 LAYER M3  ;
    ANTENNAPARTIALMETALSIDEAREA 0.1232 LAYER M3  ;
    ANTENNAMODEL OXIDE1 ;
    ANTENNAGATEAREA 0.1092 LAYER M3  ;
    ANTENNAMAXAREACAR 4.94643 LAYER M3  ;
    ANTENNAMAXSIDEAREACAR 20.8443 LAYER M3  ;
    ANTENNAMAXCUTCAR 0.18315 LAYER VIA3  ;
    PORT
      LAYER M3 ;
        RECT 0.000000 36.910000 0.600000 37.090000 ;
    END
  END y[4]
  PIN y[3]
    DIRECTION INPUT ;
    USE SIGNAL ;
    ANTENNAPARTIALMETALAREA 0.409 LAYER M3  ;
    ANTENNAPARTIALMETALSIDEAREA 1.8436 LAYER M3  ;
    ANTENNAMODEL OXIDE1 ;
    ANTENNAGATEAREA 0.0996 LAYER M3  ;
    ANTENNAMAXAREACAR 6.63655 LAYER M3  ;
    ANTENNAMAXSIDEAREACAR 29.4337 LAYER M3  ;
    ANTENNAMAXCUTCAR 0.200803 LAYER VIA3  ;
    PORT
      LAYER M3 ;
        RECT 0.000000 35.910000 0.600000 36.090000 ;
    END
  END y[3]
  PIN y[2]
    DIRECTION INPUT ;
    USE SIGNAL ;
    ANTENNAPARTIALMETALAREA 0.569 LAYER M3  ;
    ANTENNAPARTIALMETALSIDEAREA 2.5476 LAYER M3  ;
    ANTENNAMODEL OXIDE1 ;
    ANTENNAGATEAREA 0.1092 LAYER M3  ;
    ANTENNAMAXAREACAR 6.46291 LAYER M3  ;
    ANTENNAMAXSIDEAREACAR 28.8883 LAYER M3  ;
    ANTENNAMAXCUTCAR 0.18315 LAYER VIA3  ;
    PORT
      LAYER M3 ;
        RECT 0.000000 34.910000 0.600000 35.090000 ;
    END
  END y[2]
  PIN y[1]
    DIRECTION INPUT ;
    USE SIGNAL ;
    ANTENNAPARTIALMETALAREA 0.749 LAYER M3  ;
    ANTENNAPARTIALMETALSIDEAREA 3.3396 LAYER M3  ;
    ANTENNAMODEL OXIDE1 ;
    ANTENNAGATEAREA 0.0996 LAYER M3  ;
    ANTENNAMAXAREACAR 10.0502 LAYER M3  ;
    ANTENNAMAXSIDEAREACAR 44.4538 LAYER M3  ;
    ANTENNAMAXCUTCAR 0.200803 LAYER VIA3  ;
    PORT
      LAYER M3 ;
        RECT 0.000000 33.910000 0.600000 34.090000 ;
    END
  END y[1]
  PIN y[0]
    DIRECTION INPUT ;
    USE SIGNAL ;
    ANTENNAPARTIALMETALAREA 0.419 LAYER M3  ;
    ANTENNAPARTIALMETALSIDEAREA 1.8436 LAYER M3  ;
    ANTENNAMODEL OXIDE1 ;
    ANTENNAGATEAREA 0.0996 LAYER M3  ;
    ANTENNAMAXAREACAR 5.63303 LAYER M3  ;
    ANTENNAMAXSIDEAREACAR 24.259 LAYER M3  ;
    ANTENNAMAXCUTCAR 0.200803 LAYER VIA3  ;
    PORT
      LAYER M3 ;
        RECT 0.000000 32.910000 0.600000 33.090000 ;
    END
  END y[0]
  PIN level[1]
    DIRECTION INPUT ;
    USE SIGNAL ;
    ANTENNAPARTIALMETALAREA 0.137 LAYER M3  ;
    ANTENNAPARTIALMETALSIDEAREA 0.6908 LAYER M3  ;
    ANTENNAMODEL OXIDE1 ;
    ANTENNAGATEAREA 0.0546 LAYER M3  ;
    ANTENNAMAXAREACAR 4.72527 LAYER M3  ;
    ANTENNAMAXSIDEAREACAR 21.1429 LAYER M3  ;
    ANTENNAMAXCUTCAR 0.3663 LAYER VIA3  ;
    PORT
      LAYER M3 ;
        RECT 13.910000 332.200000 14.090000 332.800000 ;
    END
  END level[1]
  PIN level[0]
    DIRECTION INPUT ;
    USE SIGNAL ;
    ANTENNAPARTIALMETALAREA 0.277 LAYER M3  ;
    ANTENNAPARTIALMETALSIDEAREA 1.3068 LAYER M3  ;
    ANTENNAMODEL OXIDE1 ;
    ANTENNAGATEAREA 0.0546 LAYER M3  ;
    ANTENNAMAXAREACAR 7.0696 LAYER M3  ;
    ANTENNAMAXSIDEAREACAR 32.1612 LAYER M3  ;
    ANTENNAMAXCUTCAR 0.3663 LAYER VIA3  ;
    PORT
      LAYER M3 ;
        RECT 11.910000 332.200000 12.090000 332.800000 ;
    END
  END level[0]
  PIN divide_mode
    DIRECTION INPUT ;
    USE SIGNAL ;
    ANTENNAPARTIALMETALAREA 0.137 LAYER M3  ;
    ANTENNAPARTIALMETALSIDEAREA 0.6908 LAYER M3  ;
    ANTENNAMODEL OXIDE1 ;
    ANTENNAGATEAREA 0.0246 LAYER M3  ;
    ANTENNAMAXAREACAR 9.87805 LAYER M3  ;
    ANTENNAMAXSIDEAREACAR 46.1951 LAYER M3  ;
    ANTENNAMAXCUTCAR 0.813008 LAYER VIA3  ;
    PORT
      LAYER M3 ;
        RECT 9.910000 332.200000 10.090000 332.800000 ;
    END
  END divide_mode
  PIN result[31]
    DIRECTION OUTPUT ;
    USE SIGNAL ;
    ANTENNAPARTIALMETALAREA 0.239 LAYER M3  ;
    ANTENNAPARTIALMETALSIDEAREA 1.0516 LAYER M3  ;
    ANTENNAPARTIALCUTAREA 0.01 LAYER VIA3  ;
    ANTENNAPARTIALMETALAREA 0.058 LAYER M4  ;
    ANTENNAPARTIALMETALSIDEAREA 0.2992 LAYER M4  ;
    ANTENNAPARTIALCUTAREA 0.01 LAYER VIA4  ;
    ANTENNADIFFAREA 0.077 LAYER M5  ;
    ANTENNAPARTIALMETALAREA 2.558 LAYER M5  ;
    ANTENNAPARTIALMETALSIDEAREA 11.2992 LAYER M5  ;
    PORT
      LAYER M3 ;
        RECT 118.200000 32.110000 118.800000 32.290000 ;
    END
  END result[31]
  PIN result[30]
    DIRECTION OUTPUT ;
    USE SIGNAL ;
    ANTENNAPARTIALMETALAREA 0.737 LAYER M3  ;
    ANTENNAPARTIALMETALSIDEAREA 3.2868 LAYER M3  ;
    ANTENNAPARTIALCUTAREA 0.01 LAYER VIA3  ;
    ANTENNADIFFAREA 0.077 LAYER M4  ;
    ANTENNAPARTIALMETALAREA 0.238 LAYER M4  ;
    ANTENNAPARTIALMETALSIDEAREA 1.0912 LAYER M4  ;
    PORT
      LAYER M3 ;
        RECT 118.200000 31.110000 118.800000 31.290000 ;
    END
  END result[30]
  PIN result[29]
    DIRECTION OUTPUT ;
    USE SIGNAL ;
    ANTENNAPARTIALCUTAREA 0.01 LAYER VIA3  ;
    ANTENNAPARTIALMETALAREA 0.338 LAYER M4  ;
    ANTENNAPARTIALMETALSIDEAREA 1.5312 LAYER M4  ;
    ANTENNAPARTIALCUTAREA 0.01 LAYER VIA4  ;
    ANTENNADIFFAREA 0.077 LAYER M5  ;
    ANTENNAPARTIALMETALAREA 1.998 LAYER M5  ;
    ANTENNAPARTIALMETALSIDEAREA 8.8352 LAYER M5  ;
    PORT
      LAYER M3 ;
        RECT 118.200000 30.110000 118.800000 30.290000 ;
    END
  END result[29]
  PIN result[28]
    DIRECTION OUTPUT ;
    USE SIGNAL ;
    ANTENNAPARTIALMETALAREA 0.159 LAYER M3  ;
    ANTENNAPARTIALMETALSIDEAREA 0.6996 LAYER M3  ;
    ANTENNAPARTIALCUTAREA 0.01 LAYER VIA3  ;
    ANTENNAPARTIALMETALAREA 0.798 LAYER M4  ;
    ANTENNAPARTIALMETALSIDEAREA 3.5552 LAYER M4  ;
    ANTENNAPARTIALCUTAREA 0.01 LAYER VIA4  ;
    ANTENNADIFFAREA 0.0678 LAYER M5  ;
    ANTENNAPARTIALMETALAREA 1.978 LAYER M5  ;
    ANTENNAPARTIALMETALSIDEAREA 8.7472 LAYER M5  ;
    PORT
      LAYER M3 ;
        RECT 118.200000 29.110000 118.800000 29.290000 ;
    END
  END result[28]
  PIN result[27]
    DIRECTION OUTPUT ;
    USE SIGNAL ;
    ANTENNAPARTIALMETALAREA 0.319 LAYER M3  ;
    ANTENNAPARTIALMETALSIDEAREA 1.4036 LAYER M3  ;
    ANTENNAPARTIALCUTAREA 0.01 LAYER VIA3  ;
    ANTENNAPARTIALMETALAREA 0.338 LAYER M4  ;
    ANTENNAPARTIALMETALSIDEAREA 1.5312 LAYER M4  ;
    ANTENNAPARTIALCUTAREA 0.01 LAYER VIA4  ;
    ANTENNADIFFAREA 0.077 LAYER M5  ;
    ANTENNAPARTIALMETALAREA 1.538 LAYER M5  ;
    ANTENNAPARTIALMETALSIDEAREA 6.8112 LAYER M5  ;
    PORT
      LAYER M3 ;
        RECT 118.200000 28.110000 118.800000 28.290000 ;
    END
  END result[27]
  PIN result[26]
    DIRECTION OUTPUT ;
    USE SIGNAL ;
    ANTENNADIFFAREA 0.077 LAYER M3  ;
    ANTENNAPARTIALMETALAREA 2.025 LAYER M3  ;
    ANTENNAPARTIALMETALSIDEAREA 9.042 LAYER M3  ;
    PORT
      LAYER M3 ;
        RECT 118.200000 27.110000 118.800000 27.290000 ;
    END
  END result[26]
  PIN result[25]
    DIRECTION OUTPUT ;
    USE SIGNAL ;
    ANTENNAPARTIALCUTAREA 0.01 LAYER VIA3  ;
    ANTENNAPARTIALMETALAREA 0.298 LAYER M4  ;
    ANTENNAPARTIALMETALSIDEAREA 1.3552 LAYER M4  ;
    ANTENNAPARTIALCUTAREA 0.01 LAYER VIA4  ;
    ANTENNADIFFAREA 0.077 LAYER M5  ;
    ANTENNAPARTIALMETALAREA 2.598 LAYER M5  ;
    ANTENNAPARTIALMETALSIDEAREA 11.4752 LAYER M5  ;
    PORT
      LAYER M3 ;
        RECT 118.200000 26.110000 118.800000 26.290000 ;
    END
  END result[25]
  PIN result[24]
    DIRECTION OUTPUT ;
    USE SIGNAL ;
    ANTENNADIFFAREA 0.077 LAYER M3  ;
    ANTENNAPARTIALMETALAREA 1.887 LAYER M3  ;
    ANTENNAPARTIALMETALSIDEAREA 8.3908 LAYER M3  ;
    PORT
      LAYER M3 ;
        RECT 118.200000 25.110000 118.800000 25.290000 ;
    END
  END result[24]
  PIN result[23]
    DIRECTION OUTPUT ;
    USE SIGNAL ;
    ANTENNADIFFAREA 0.077 LAYER M3  ;
    ANTENNAPARTIALMETALAREA 1.176 LAYER M3  ;
    ANTENNAPARTIALMETALSIDEAREA 5.2624 LAYER M3  ;
    PORT
      LAYER M3 ;
        RECT 118.200000 24.110000 118.800000 24.290000 ;
    END
  END result[23]
  PIN result[22]
    DIRECTION OUTPUT ;
    USE SIGNAL ;
    ANTENNAPARTIALMETALAREA 0.279 LAYER M3  ;
    ANTENNAPARTIALMETALSIDEAREA 1.2276 LAYER M3  ;
    ANTENNAPARTIALCUTAREA 0.01 LAYER VIA3  ;
    ANTENNAPARTIALMETALAREA 0.078 LAYER M4  ;
    ANTENNAPARTIALMETALSIDEAREA 0.3872 LAYER M4  ;
    ANTENNAPARTIALCUTAREA 0.01 LAYER VIA4  ;
    ANTENNADIFFAREA 0.077 LAYER M5  ;
    ANTENNAPARTIALMETALAREA 1.938 LAYER M5  ;
    ANTENNAPARTIALMETALSIDEAREA 8.5712 LAYER M5  ;
    PORT
      LAYER M3 ;
        RECT 118.200000 23.110000 118.800000 23.290000 ;
    END
  END result[22]
  PIN result[21]
    DIRECTION OUTPUT ;
    USE SIGNAL ;
    ANTENNAPARTIALMETALAREA 2.579 LAYER M3  ;
    ANTENNAPARTIALMETALSIDEAREA 11.3476 LAYER M3  ;
    ANTENNAPARTIALCUTAREA 0.01 LAYER VIA3  ;
    ANTENNADIFFAREA 0.077 LAYER M4  ;
    ANTENNAPARTIALMETALAREA 0.838 LAYER M4  ;
    ANTENNAPARTIALMETALSIDEAREA 3.7312 LAYER M4  ;
    PORT
      LAYER M3 ;
        RECT 118.200000 22.110000 118.800000 22.290000 ;
    END
  END result[21]
  PIN result[20]
    DIRECTION OUTPUT ;
    USE SIGNAL ;
    ANTENNAPARTIALCUTAREA 0.01 LAYER VIA3  ;
    ANTENNAPARTIALMETALAREA 0.178 LAYER M4  ;
    ANTENNAPARTIALMETALSIDEAREA 0.8272 LAYER M4  ;
    ANTENNAPARTIALCUTAREA 0.01 LAYER VIA4  ;
    ANTENNADIFFAREA 0.077 LAYER M5  ;
    ANTENNAPARTIALMETALAREA 2.658 LAYER M5  ;
    ANTENNAPARTIALMETALSIDEAREA 11.7392 LAYER M5  ;
    PORT
      LAYER M3 ;
        RECT 118.200000 21.110000 118.800000 21.290000 ;
    END
  END result[20]
  PIN result[19]
    DIRECTION OUTPUT ;
    USE SIGNAL ;
    ANTENNADIFFAREA 0.077 LAYER M3  ;
    ANTENNAPARTIALMETALAREA 1.429 LAYER M3  ;
    ANTENNAPARTIALMETALSIDEAREA 6.3316 LAYER M3  ;
    PORT
      LAYER M3 ;
        RECT 118.200000 20.110000 118.800000 20.290000 ;
    END
  END result[19]
  PIN result[18]
    DIRECTION OUTPUT ;
    USE SIGNAL ;
    ANTENNAPARTIALMETALAREA 0.371 LAYER M3  ;
    ANTENNAPARTIALMETALSIDEAREA 1.6764 LAYER M3  ;
    ANTENNAPARTIALCUTAREA 0.01 LAYER VIA3  ;
    ANTENNAPARTIALMETALAREA 0.052 LAYER M4  ;
    ANTENNAPARTIALMETALSIDEAREA 0.2728 LAYER M4  ;
    ANTENNAPARTIALCUTAREA 0.01 LAYER VIA4  ;
    ANTENNADIFFAREA 0.077 LAYER M5  ;
    ANTENNAPARTIALMETALAREA 1.218 LAYER M5  ;
    ANTENNAPARTIALMETALSIDEAREA 5.4032 LAYER M5  ;
    PORT
      LAYER M3 ;
        RECT 118.200000 19.110000 118.800000 19.290000 ;
    END
  END result[18]
  PIN result[17]
    DIRECTION OUTPUT ;
    USE SIGNAL ;
    ANTENNAPARTIALMETALAREA 1.579 LAYER M3  ;
    ANTENNAPARTIALMETALSIDEAREA 6.9476 LAYER M3  ;
    ANTENNAPARTIALCUTAREA 0.01 LAYER VIA3  ;
    ANTENNADIFFAREA 0.1502 LAYER M4  ;
    ANTENNAPARTIALMETALAREA 0.098 LAYER M4  ;
    ANTENNAPARTIALMETALSIDEAREA 0.4752 LAYER M4  ;
    PORT
      LAYER M3 ;
        RECT 118.200000 18.110000 118.800000 18.290000 ;
    END
  END result[17]
  PIN result[16]
    DIRECTION OUTPUT ;
    USE SIGNAL ;
    ANTENNAPARTIALMETALAREA 2 LAYER M3  ;
    ANTENNAPARTIALMETALSIDEAREA 8.8 LAYER M3  ;
    ANTENNAPARTIALCUTAREA 0.01 LAYER VIA3  ;
    ANTENNADIFFAREA 0.077 LAYER M4  ;
    ANTENNAPARTIALMETALAREA 1.278 LAYER M4  ;
    ANTENNAPARTIALMETALSIDEAREA 5.6672 LAYER M4  ;
    PORT
      LAYER M3 ;
        RECT 118.200000 17.110000 118.800000 17.290000 ;
    END
  END result[16]
  PIN result[15]
    DIRECTION OUTPUT ;
    USE SIGNAL ;
    ANTENNADIFFAREA 0.077 LAYER M3  ;
    ANTENNAPARTIALMETALAREA 1.849 LAYER M3  ;
    ANTENNAPARTIALMETALSIDEAREA 8.1796 LAYER M3  ;
    PORT
      LAYER M3 ;
        RECT 118.200000 16.110000 118.800000 16.290000 ;
    END
  END result[15]
  PIN result[14]
    DIRECTION OUTPUT ;
    USE SIGNAL ;
    ANTENNAPARTIALMETALAREA 1.739 LAYER M3  ;
    ANTENNAPARTIALMETALSIDEAREA 7.6516 LAYER M3  ;
    ANTENNAPARTIALCUTAREA 0.01 LAYER VIA3  ;
    ANTENNADIFFAREA 0.077 LAYER M4  ;
    ANTENNAPARTIALMETALAREA 1.498 LAYER M4  ;
    ANTENNAPARTIALMETALSIDEAREA 6.6352 LAYER M4  ;
    PORT
      LAYER M3 ;
        RECT 118.200000 15.110000 118.800000 15.290000 ;
    END
  END result[14]
  PIN result[13]
    DIRECTION OUTPUT ;
    USE SIGNAL ;
    ANTENNAPARTIALMETALAREA 0.579 LAYER M3  ;
    ANTENNAPARTIALMETALSIDEAREA 2.5476 LAYER M3  ;
    ANTENNAPARTIALCUTAREA 0.01 LAYER VIA3  ;
    ANTENNADIFFAREA 0.077 LAYER M4  ;
    ANTENNAPARTIALMETALAREA 0.778 LAYER M4  ;
    ANTENNAPARTIALMETALSIDEAREA 3.4672 LAYER M4  ;
    PORT
      LAYER M3 ;
        RECT 118.200000 14.110000 118.800000 14.290000 ;
    END
  END result[13]
  PIN result[12]
    DIRECTION OUTPUT ;
    USE SIGNAL ;
    ANTENNAPARTIALMETALAREA 0.019 LAYER M3  ;
    ANTENNAPARTIALMETALSIDEAREA 0.0836 LAYER M3  ;
    ANTENNAPARTIALCUTAREA 0.01 LAYER VIA3  ;
    ANTENNADIFFAREA 0.077 LAYER M4  ;
    ANTENNAPARTIALMETALAREA 1.176 LAYER M4  ;
    ANTENNAPARTIALMETALSIDEAREA 5.2624 LAYER M4  ;
    PORT
      LAYER M3 ;
        RECT 118.200000 13.110000 118.800000 13.290000 ;
    END
  END result[12]
  PIN result[11]
    DIRECTION OUTPUT ;
    USE SIGNAL ;
    ANTENNAPARTIALMETALAREA 0.379 LAYER M3  ;
    ANTENNAPARTIALMETALSIDEAREA 1.6676 LAYER M3  ;
    ANTENNAPARTIALCUTAREA 0.01 LAYER VIA3  ;
    ANTENNADIFFAREA 0.1502 LAYER M4  ;
    ANTENNAPARTIALMETALAREA 3.618 LAYER M4  ;
    ANTENNAPARTIALMETALSIDEAREA 15.9632 LAYER M4  ;
    PORT
      LAYER M3 ;
        RECT 118.200000 12.110000 118.800000 12.290000 ;
    END
  END result[11]
  PIN result[10]
    DIRECTION OUTPUT ;
    USE SIGNAL ;
    ANTENNADIFFAREA 0.077 LAYER M3  ;
    ANTENNAPARTIALMETALAREA 1.387 LAYER M3  ;
    ANTENNAPARTIALMETALSIDEAREA 6.1908 LAYER M3  ;
    PORT
      LAYER M3 ;
        RECT 118.200000 11.110000 118.800000 11.290000 ;
    END
  END result[10]
  PIN result[9]
    DIRECTION OUTPUT ;
    USE SIGNAL ;
    ANTENNAPARTIALMETALAREA 0.719 LAYER M3  ;
    ANTENNAPARTIALMETALSIDEAREA 3.1636 LAYER M3  ;
    ANTENNAPARTIALCUTAREA 0.01 LAYER VIA3  ;
    ANTENNADIFFAREA 0.077 LAYER M4  ;
    ANTENNAPARTIALMETALAREA 1.178 LAYER M4  ;
    ANTENNAPARTIALMETALSIDEAREA 5.2272 LAYER M4  ;
    PORT
      LAYER M3 ;
        RECT 118.200000 10.110000 118.800000 10.290000 ;
    END
  END result[9]
  PIN result[8]
    DIRECTION OUTPUT ;
    USE SIGNAL ;
    ANTENNADIFFAREA 0.077 LAYER M3  ;
    ANTENNAPARTIALMETALAREA 0.727 LAYER M3  ;
    ANTENNAPARTIALMETALSIDEAREA 3.2868 LAYER M3  ;
    PORT
      LAYER M3 ;
        RECT 118.200000 9.110000 118.800000 9.290000 ;
    END
  END result[8]
  PIN result[7]
    DIRECTION OUTPUT ;
    USE SIGNAL ;
    ANTENNAPARTIALMETALAREA 0.459 LAYER M3  ;
    ANTENNAPARTIALMETALSIDEAREA 2.0196 LAYER M3  ;
    ANTENNAPARTIALCUTAREA 0.01 LAYER VIA3  ;
    ANTENNADIFFAREA 0.077 LAYER M4  ;
    ANTENNAPARTIALMETALAREA 1.838 LAYER M4  ;
    ANTENNAPARTIALMETALSIDEAREA 8.1312 LAYER M4  ;
    PORT
      LAYER M3 ;
        RECT 118.200000 8.110000 118.800000 8.290000 ;
    END
  END result[7]
  PIN result[6]
    DIRECTION OUTPUT ;
    USE SIGNAL ;
    ANTENNADIFFAREA 0.0678 LAYER M3  ;
    ANTENNAPARTIALMETALAREA 0.627 LAYER M3  ;
    ANTENNAPARTIALMETALSIDEAREA 2.8468 LAYER M3  ;
    PORT
      LAYER M3 ;
        RECT 118.200000 7.110000 118.800000 7.290000 ;
    END
  END result[6]
  PIN result[5]
    DIRECTION OUTPUT ;
    USE SIGNAL ;
    ANTENNADIFFAREA 0.1502 LAYER M3  ;
    ANTENNAPARTIALMETALAREA 0.029 LAYER M3  ;
    ANTENNAPARTIALMETALSIDEAREA 0.1716 LAYER M3  ;
    PORT
      LAYER M3 ;
        RECT 118.200000 6.110000 118.800000 6.290000 ;
    END
  END result[5]
  PIN result[4]
    DIRECTION OUTPUT ;
    USE SIGNAL ;
    ANTENNAPARTIALMETALAREA 1.059 LAYER M3  ;
    ANTENNAPARTIALMETALSIDEAREA 4.6596 LAYER M3  ;
    ANTENNAPARTIALCUTAREA 0.01 LAYER VIA3  ;
    ANTENNADIFFAREA 0.077 LAYER M4  ;
    ANTENNAPARTIALMETALAREA 1.238 LAYER M4  ;
    ANTENNAPARTIALMETALSIDEAREA 5.4912 LAYER M4  ;
    PORT
      LAYER M3 ;
        RECT 118.200000 5.110000 118.800000 5.290000 ;
    END
  END result[4]
  PIN result[3]
    DIRECTION OUTPUT ;
    USE SIGNAL ;
    ANTENNAPARTIALMETALAREA 1.439 LAYER M3  ;
    ANTENNAPARTIALMETALSIDEAREA 6.3316 LAYER M3  ;
    ANTENNAPARTIALCUTAREA 0.01 LAYER VIA3  ;
    ANTENNADIFFAREA 0.077 LAYER M4  ;
    ANTENNAPARTIALMETALAREA 1.718 LAYER M4  ;
    ANTENNAPARTIALMETALSIDEAREA 7.6032 LAYER M4  ;
    PORT
      LAYER M3 ;
        RECT 118.200000 4.110000 118.800000 4.290000 ;
    END
  END result[3]
  PIN result[2]
    DIRECTION OUTPUT ;
    USE SIGNAL ;
    ANTENNADIFFAREA 0.0678 LAYER M3  ;
    ANTENNAPARTIALMETALAREA 1.007 LAYER M3  ;
    ANTENNAPARTIALMETALSIDEAREA 4.5188 LAYER M3  ;
    PORT
      LAYER M3 ;
        RECT 118.200000 3.110000 118.800000 3.290000 ;
    END
  END result[2]
  PIN result[1]
    DIRECTION OUTPUT ;
    USE SIGNAL ;
    ANTENNAPARTIALMETALAREA 1.659 LAYER M3  ;
    ANTENNAPARTIALMETALSIDEAREA 7.2996 LAYER M3  ;
    ANTENNAPARTIALCUTAREA 0.01 LAYER VIA3  ;
    ANTENNADIFFAREA 0.077 LAYER M4  ;
    ANTENNAPARTIALMETALAREA 1.178 LAYER M4  ;
    ANTENNAPARTIALMETALSIDEAREA 5.2272 LAYER M4  ;
    PORT
      LAYER M3 ;
        RECT 118.200000 2.110000 118.800000 2.290000 ;
    END
  END result[1]
  PIN result[0]
    DIRECTION OUTPUT ;
    USE SIGNAL ;
    ANTENNADIFFAREA 0.0678 LAYER M3  ;
    ANTENNAPARTIALMETALAREA 1.007 LAYER M3  ;
    ANTENNAPARTIALMETALSIDEAREA 4.5188 LAYER M3  ;
    PORT
      LAYER M3 ;
        RECT 118.200000 1.110000 118.800000 1.290000 ;
    END
  END result[0]
  PIN VDD
    DIRECTION INOUT ;
    USE POWER ;
    PORT
      LAYER M6 ;
        RECT 12.000000 0.000000 13.000000 1.000000 ;
    END
    PORT
      LAYER M6 ;
        RECT 12.000000 331.800000 13.000000 332.800000 ;
    END
    PORT
      LAYER M6 ;
        RECT 24.000000 0.000000 25.000000 1.000000 ;
    END
    PORT
      LAYER M6 ;
        RECT 24.000000 331.800000 25.000000 332.800000 ;
    END
    PORT
      LAYER M6 ;
        RECT 36.000000 0.000000 37.000000 1.000000 ;
    END
    PORT
      LAYER M6 ;
        RECT 36.000000 331.800000 37.000000 332.800000 ;
    END
    PORT
      LAYER M6 ;
        RECT 48.000000 0.000000 49.000000 1.000000 ;
    END
    PORT
      LAYER M6 ;
        RECT 48.000000 331.800000 49.000000 332.800000 ;
    END
    PORT
      LAYER M6 ;
        RECT 60.000000 0.000000 61.000000 1.000000 ;
    END
    PORT
      LAYER M6 ;
        RECT 60.000000 331.800000 61.000000 332.800000 ;
    END
    PORT
      LAYER M6 ;
        RECT 72.000000 0.000000 73.000000 1.000000 ;
    END
    PORT
      LAYER M6 ;
        RECT 72.000000 331.800000 73.000000 332.800000 ;
    END
    PORT
      LAYER M6 ;
        RECT 84.000000 0.000000 85.000000 1.000000 ;
    END
    PORT
      LAYER M6 ;
        RECT 84.000000 331.800000 85.000000 332.800000 ;
    END
    PORT
      LAYER M6 ;
        RECT 96.000000 0.000000 97.000000 1.000000 ;
    END
    PORT
      LAYER M6 ;
        RECT 96.000000 331.800000 97.000000 332.800000 ;
    END
    PORT
      LAYER M6 ;
        RECT 108.000000 0.000000 109.000000 1.000000 ;
    END
    PORT
      LAYER M6 ;
        RECT 108.000000 331.800000 109.000000 332.800000 ;
    END
    PORT
      LAYER M6 ;
        RECT 115.350000 331.800000 116.350000 332.800000 ;
    END
    PORT
      LAYER M6 ;
        RECT 115.350000 0.000000 116.350000 1.000000 ;
    END
    PORT
      LAYER M6 ;
        RECT 2.450000 331.800000 3.450000 332.800000 ;
    END
    PORT
      LAYER M6 ;
        RECT 2.450000 0.000000 3.450000 1.000000 ;
    END

# P/G power stripe data as pin
    PORT
      LAYER M6 ;
        RECT 2.450000 0.000000 3.450000 332.800000 ;
        RECT 12.000000 0.000000 13.000000 332.800000 ;
        RECT 24.000000 0.000000 25.000000 332.800000 ;
        RECT 36.000000 0.000000 37.000000 332.800000 ;
        RECT 48.000000 0.000000 49.000000 332.800000 ;
        RECT 60.000000 0.000000 61.000000 332.800000 ;
        RECT 72.000000 0.000000 73.000000 332.800000 ;
        RECT 84.000000 0.000000 85.000000 332.800000 ;
        RECT 96.000000 0.000000 97.000000 332.800000 ;
        RECT 115.350000 0.000000 116.350000 332.800000 ;
        RECT 108.000000 0.000000 109.000000 332.800000 ;
    END
# end of P/G power stripe data as pin

  END VDD
  PIN VSS
    DIRECTION INOUT ;
    USE GROUND ;
    PORT
      LAYER M6 ;
        RECT 13.500000 0.000000 14.500000 1.000000 ;
    END
    PORT
      LAYER M6 ;
        RECT 13.500000 331.800000 14.500000 332.800000 ;
    END
    PORT
      LAYER M6 ;
        RECT 25.500000 0.000000 26.500000 1.000000 ;
    END
    PORT
      LAYER M6 ;
        RECT 25.500000 331.800000 26.500000 332.800000 ;
    END
    PORT
      LAYER M6 ;
        RECT 37.500000 0.000000 38.500000 1.000000 ;
    END
    PORT
      LAYER M6 ;
        RECT 37.500000 331.800000 38.500000 332.800000 ;
    END
    PORT
      LAYER M6 ;
        RECT 49.500000 0.000000 50.500000 1.000000 ;
    END
    PORT
      LAYER M6 ;
        RECT 49.500000 331.800000 50.500000 332.800000 ;
    END
    PORT
      LAYER M6 ;
        RECT 61.500000 0.000000 62.500000 1.000000 ;
    END
    PORT
      LAYER M6 ;
        RECT 61.500000 331.800000 62.500000 332.800000 ;
    END
    PORT
      LAYER M6 ;
        RECT 73.500000 0.000000 74.500000 1.000000 ;
    END
    PORT
      LAYER M6 ;
        RECT 73.500000 331.800000 74.500000 332.800000 ;
    END
    PORT
      LAYER M6 ;
        RECT 85.500000 0.000000 86.500000 1.000000 ;
    END
    PORT
      LAYER M6 ;
        RECT 85.500000 331.800000 86.500000 332.800000 ;
    END
    PORT
      LAYER M6 ;
        RECT 97.500000 0.000000 98.500000 1.000000 ;
    END
    PORT
      LAYER M6 ;
        RECT 97.500000 331.800000 98.500000 332.800000 ;
    END
    PORT
      LAYER M6 ;
        RECT 109.500000 0.000000 110.500000 1.000000 ;
    END
    PORT
      LAYER M6 ;
        RECT 109.500000 331.800000 110.500000 332.800000 ;
    END
    PORT
      LAYER M6 ;
        RECT 116.850000 331.800000 117.850000 332.800000 ;
    END
    PORT
      LAYER M6 ;
        RECT 116.850000 0.000000 117.850000 1.000000 ;
    END
    PORT
      LAYER M6 ;
        RECT 0.950000 331.800000 1.950000 332.800000 ;
    END
    PORT
      LAYER M6 ;
        RECT 0.950000 0.000000 1.950000 1.000000 ;
    END

# P/G power stripe data as pin
    PORT
      LAYER M6 ;
        RECT 0.950000 0.000000 1.950000 332.800000 ;
        RECT 13.500000 0.000000 14.500000 332.800000 ;
        RECT 25.500000 0.000000 26.500000 332.800000 ;
        RECT 37.500000 0.000000 38.500000 332.800000 ;
        RECT 49.500000 0.000000 50.500000 332.800000 ;
        RECT 61.500000 0.000000 62.500000 332.800000 ;
        RECT 73.500000 0.000000 74.500000 332.800000 ;
        RECT 85.500000 0.000000 86.500000 332.800000 ;
        RECT 97.500000 0.000000 98.500000 332.800000 ;
        RECT 116.850000 0.000000 117.850000 332.800000 ;
        RECT 109.500000 0.000000 110.500000 332.800000 ;
    END
# end of P/G power stripe data as pin

  END VSS
  OBS
    LAYER M1 ;
      RECT 0.000000 0.000000 118.800000 332.800000 ;
    LAYER M2 ;
      RECT 0.000000 0.000000 118.800000 332.800000 ;
    LAYER M3 ;
      RECT 16.250000 332.040000 118.800000 332.800000 ;
      RECT 14.250000 332.040000 15.750000 332.800000 ;
      RECT 12.250000 332.040000 13.750000 332.800000 ;
      RECT 10.250000 332.040000 11.750000 332.800000 ;
      RECT 0.000000 332.040000 9.750000 332.800000 ;
      RECT 0.000000 64.190000 118.800000 332.040000 ;
      RECT 0.700000 63.810000 118.800000 64.190000 ;
      RECT 0.000000 63.190000 118.800000 63.810000 ;
      RECT 0.700000 62.810000 118.800000 63.190000 ;
      RECT 0.000000 62.190000 118.800000 62.810000 ;
      RECT 0.700000 61.810000 118.800000 62.190000 ;
      RECT 0.000000 61.190000 118.800000 61.810000 ;
      RECT 0.700000 60.810000 118.800000 61.190000 ;
      RECT 0.000000 60.190000 118.800000 60.810000 ;
      RECT 0.700000 59.810000 118.800000 60.190000 ;
      RECT 0.000000 59.190000 118.800000 59.810000 ;
      RECT 0.700000 58.810000 118.800000 59.190000 ;
      RECT 0.000000 58.190000 118.800000 58.810000 ;
      RECT 0.700000 57.810000 118.800000 58.190000 ;
      RECT 0.000000 57.190000 118.800000 57.810000 ;
      RECT 0.700000 56.810000 118.800000 57.190000 ;
      RECT 0.000000 56.190000 118.800000 56.810000 ;
      RECT 0.700000 55.810000 118.800000 56.190000 ;
      RECT 0.000000 55.190000 118.800000 55.810000 ;
      RECT 0.700000 54.810000 118.800000 55.190000 ;
      RECT 0.000000 54.190000 118.800000 54.810000 ;
      RECT 0.700000 53.810000 118.800000 54.190000 ;
      RECT 0.000000 53.190000 118.800000 53.810000 ;
      RECT 0.700000 52.810000 118.800000 53.190000 ;
      RECT 0.000000 52.190000 118.800000 52.810000 ;
      RECT 0.700000 51.810000 118.800000 52.190000 ;
      RECT 0.000000 51.190000 118.800000 51.810000 ;
      RECT 0.700000 50.810000 118.800000 51.190000 ;
      RECT 0.000000 50.190000 118.800000 50.810000 ;
      RECT 0.700000 49.810000 118.800000 50.190000 ;
      RECT 0.000000 49.190000 118.800000 49.810000 ;
      RECT 0.700000 48.810000 118.800000 49.190000 ;
      RECT 0.000000 48.190000 118.800000 48.810000 ;
      RECT 0.700000 47.810000 118.800000 48.190000 ;
      RECT 0.000000 47.190000 118.800000 47.810000 ;
      RECT 0.700000 46.810000 118.800000 47.190000 ;
      RECT 0.000000 46.190000 118.800000 46.810000 ;
      RECT 0.700000 45.810000 118.800000 46.190000 ;
      RECT 0.000000 45.190000 118.800000 45.810000 ;
      RECT 0.700000 44.810000 118.800000 45.190000 ;
      RECT 0.000000 44.190000 118.800000 44.810000 ;
      RECT 0.700000 43.810000 118.800000 44.190000 ;
      RECT 0.000000 43.190000 118.800000 43.810000 ;
      RECT 0.700000 42.810000 118.800000 43.190000 ;
      RECT 0.000000 42.190000 118.800000 42.810000 ;
      RECT 0.700000 41.810000 118.800000 42.190000 ;
      RECT 0.000000 41.190000 118.800000 41.810000 ;
      RECT 0.700000 40.810000 118.800000 41.190000 ;
      RECT 0.000000 40.190000 118.800000 40.810000 ;
      RECT 0.700000 39.810000 118.800000 40.190000 ;
      RECT 0.000000 39.190000 118.800000 39.810000 ;
      RECT 0.700000 38.810000 118.800000 39.190000 ;
      RECT 0.000000 38.190000 118.800000 38.810000 ;
      RECT 0.700000 37.810000 118.800000 38.190000 ;
      RECT 0.000000 37.190000 118.800000 37.810000 ;
      RECT 0.700000 36.810000 118.800000 37.190000 ;
      RECT 0.000000 36.190000 118.800000 36.810000 ;
      RECT 0.700000 35.810000 118.800000 36.190000 ;
      RECT 0.000000 35.190000 118.800000 35.810000 ;
      RECT 0.700000 34.810000 118.800000 35.190000 ;
      RECT 0.000000 34.190000 118.800000 34.810000 ;
      RECT 0.700000 33.810000 118.800000 34.190000 ;
      RECT 0.000000 33.190000 118.800000 33.810000 ;
      RECT 0.700000 32.810000 118.800000 33.190000 ;
      RECT 0.000000 32.390000 118.800000 32.810000 ;
      RECT 0.000000 32.190000 118.100000 32.390000 ;
      RECT 0.700000 32.010000 118.100000 32.190000 ;
      RECT 0.700000 31.810000 118.800000 32.010000 ;
      RECT 0.000000 31.390000 118.800000 31.810000 ;
      RECT 0.000000 31.190000 118.100000 31.390000 ;
      RECT 0.700000 31.010000 118.100000 31.190000 ;
      RECT 0.700000 30.810000 118.800000 31.010000 ;
      RECT 0.000000 30.390000 118.800000 30.810000 ;
      RECT 0.000000 30.190000 118.100000 30.390000 ;
      RECT 0.700000 30.010000 118.100000 30.190000 ;
      RECT 0.700000 29.810000 118.800000 30.010000 ;
      RECT 0.000000 29.390000 118.800000 29.810000 ;
      RECT 0.000000 29.190000 118.100000 29.390000 ;
      RECT 0.700000 29.010000 118.100000 29.190000 ;
      RECT 0.700000 28.810000 118.800000 29.010000 ;
      RECT 0.000000 28.390000 118.800000 28.810000 ;
      RECT 0.000000 28.190000 118.100000 28.390000 ;
      RECT 0.700000 28.010000 118.100000 28.190000 ;
      RECT 0.700000 27.810000 118.800000 28.010000 ;
      RECT 0.000000 27.390000 118.800000 27.810000 ;
      RECT 0.000000 27.190000 118.100000 27.390000 ;
      RECT 0.700000 27.010000 118.100000 27.190000 ;
      RECT 0.700000 26.810000 118.800000 27.010000 ;
      RECT 0.000000 26.390000 118.800000 26.810000 ;
      RECT 0.000000 26.190000 118.100000 26.390000 ;
      RECT 0.700000 26.010000 118.100000 26.190000 ;
      RECT 0.700000 25.810000 118.800000 26.010000 ;
      RECT 0.000000 25.390000 118.800000 25.810000 ;
      RECT 0.000000 25.190000 118.100000 25.390000 ;
      RECT 0.700000 25.010000 118.100000 25.190000 ;
      RECT 0.700000 24.810000 118.800000 25.010000 ;
      RECT 0.000000 24.390000 118.800000 24.810000 ;
      RECT 0.000000 24.190000 118.100000 24.390000 ;
      RECT 0.700000 24.010000 118.100000 24.190000 ;
      RECT 0.700000 23.810000 118.800000 24.010000 ;
      RECT 0.000000 23.390000 118.800000 23.810000 ;
      RECT 0.000000 23.190000 118.100000 23.390000 ;
      RECT 0.700000 23.010000 118.100000 23.190000 ;
      RECT 0.700000 22.810000 118.800000 23.010000 ;
      RECT 0.000000 22.390000 118.800000 22.810000 ;
      RECT 0.000000 22.190000 118.100000 22.390000 ;
      RECT 0.700000 22.010000 118.100000 22.190000 ;
      RECT 0.700000 21.810000 118.800000 22.010000 ;
      RECT 0.000000 21.390000 118.800000 21.810000 ;
      RECT 0.000000 21.190000 118.100000 21.390000 ;
      RECT 0.700000 21.010000 118.100000 21.190000 ;
      RECT 0.700000 20.810000 118.800000 21.010000 ;
      RECT 0.000000 20.390000 118.800000 20.810000 ;
      RECT 0.000000 20.190000 118.100000 20.390000 ;
      RECT 0.700000 20.010000 118.100000 20.190000 ;
      RECT 0.700000 19.810000 118.800000 20.010000 ;
      RECT 0.000000 19.390000 118.800000 19.810000 ;
      RECT 0.000000 19.190000 118.100000 19.390000 ;
      RECT 0.700000 19.010000 118.100000 19.190000 ;
      RECT 0.700000 18.810000 118.800000 19.010000 ;
      RECT 0.000000 18.390000 118.800000 18.810000 ;
      RECT 0.000000 18.190000 118.100000 18.390000 ;
      RECT 0.700000 18.010000 118.100000 18.190000 ;
      RECT 0.700000 17.810000 118.800000 18.010000 ;
      RECT 0.000000 17.390000 118.800000 17.810000 ;
      RECT 0.000000 17.190000 118.100000 17.390000 ;
      RECT 0.700000 17.010000 118.100000 17.190000 ;
      RECT 0.700000 16.810000 118.800000 17.010000 ;
      RECT 0.000000 16.390000 118.800000 16.810000 ;
      RECT 0.000000 16.190000 118.100000 16.390000 ;
      RECT 0.700000 16.010000 118.100000 16.190000 ;
      RECT 0.700000 15.810000 118.800000 16.010000 ;
      RECT 0.000000 15.390000 118.800000 15.810000 ;
      RECT 0.000000 15.190000 118.100000 15.390000 ;
      RECT 0.700000 15.010000 118.100000 15.190000 ;
      RECT 0.700000 14.810000 118.800000 15.010000 ;
      RECT 0.000000 14.390000 118.800000 14.810000 ;
      RECT 0.000000 14.190000 118.100000 14.390000 ;
      RECT 0.700000 14.010000 118.100000 14.190000 ;
      RECT 0.700000 13.810000 118.800000 14.010000 ;
      RECT 0.000000 13.390000 118.800000 13.810000 ;
      RECT 0.000000 13.190000 118.100000 13.390000 ;
      RECT 0.700000 13.010000 118.100000 13.190000 ;
      RECT 0.700000 12.810000 118.800000 13.010000 ;
      RECT 0.000000 12.390000 118.800000 12.810000 ;
      RECT 0.000000 12.190000 118.100000 12.390000 ;
      RECT 0.700000 12.010000 118.100000 12.190000 ;
      RECT 0.700000 11.810000 118.800000 12.010000 ;
      RECT 0.000000 11.390000 118.800000 11.810000 ;
      RECT 0.000000 11.190000 118.100000 11.390000 ;
      RECT 0.700000 11.010000 118.100000 11.190000 ;
      RECT 0.700000 10.810000 118.800000 11.010000 ;
      RECT 0.000000 10.390000 118.800000 10.810000 ;
      RECT 0.000000 10.190000 118.100000 10.390000 ;
      RECT 0.700000 10.010000 118.100000 10.190000 ;
      RECT 0.700000 9.810000 118.800000 10.010000 ;
      RECT 0.000000 9.390000 118.800000 9.810000 ;
      RECT 0.000000 9.190000 118.100000 9.390000 ;
      RECT 0.700000 9.010000 118.100000 9.190000 ;
      RECT 0.700000 8.810000 118.800000 9.010000 ;
      RECT 0.000000 8.390000 118.800000 8.810000 ;
      RECT 0.000000 8.190000 118.100000 8.390000 ;
      RECT 0.700000 8.010000 118.100000 8.190000 ;
      RECT 0.700000 7.810000 118.800000 8.010000 ;
      RECT 0.000000 7.390000 118.800000 7.810000 ;
      RECT 0.000000 7.190000 118.100000 7.390000 ;
      RECT 0.700000 7.010000 118.100000 7.190000 ;
      RECT 0.700000 6.810000 118.800000 7.010000 ;
      RECT 0.000000 6.390000 118.800000 6.810000 ;
      RECT 0.000000 6.190000 118.100000 6.390000 ;
      RECT 0.700000 6.010000 118.100000 6.190000 ;
      RECT 0.700000 5.810000 118.800000 6.010000 ;
      RECT 0.000000 5.390000 118.800000 5.810000 ;
      RECT 0.000000 5.190000 118.100000 5.390000 ;
      RECT 0.700000 5.010000 118.100000 5.190000 ;
      RECT 0.700000 4.810000 118.800000 5.010000 ;
      RECT 0.000000 4.390000 118.800000 4.810000 ;
      RECT 0.000000 4.190000 118.100000 4.390000 ;
      RECT 0.700000 4.010000 118.100000 4.190000 ;
      RECT 0.700000 3.810000 118.800000 4.010000 ;
      RECT 0.000000 3.390000 118.800000 3.810000 ;
      RECT 0.000000 3.190000 118.100000 3.390000 ;
      RECT 0.700000 3.010000 118.100000 3.190000 ;
      RECT 0.700000 2.810000 118.800000 3.010000 ;
      RECT 0.000000 2.390000 118.800000 2.810000 ;
      RECT 0.000000 2.190000 118.100000 2.390000 ;
      RECT 0.700000 2.010000 118.100000 2.190000 ;
      RECT 0.700000 1.810000 118.800000 2.010000 ;
      RECT 0.000000 1.390000 118.800000 1.810000 ;
      RECT 0.000000 1.190000 118.100000 1.390000 ;
      RECT 0.700000 1.010000 118.100000 1.190000 ;
      RECT 0.700000 0.810000 118.800000 1.010000 ;
      RECT 0.000000 0.000000 118.800000 0.810000 ;
    LAYER M4 ;
      RECT 0.000000 0.000000 118.800000 332.800000 ;
    LAYER M5 ;
      RECT 0.000000 0.000000 118.800000 332.800000 ;
    LAYER M6 ;
      RECT 118.010000 0.000000 118.800000 332.800000 ;
      RECT 116.510000 0.000000 116.690000 332.800000 ;
      RECT 110.660000 0.000000 115.190000 332.800000 ;
      RECT 109.160000 0.000000 109.340000 332.800000 ;
      RECT 98.660000 0.000000 107.840000 332.800000 ;
      RECT 97.160000 0.000000 97.340000 332.800000 ;
      RECT 86.660000 0.000000 95.840000 332.800000 ;
      RECT 85.160000 0.000000 85.340000 332.800000 ;
      RECT 74.660000 0.000000 83.840000 332.800000 ;
      RECT 73.160000 0.000000 73.340000 332.800000 ;
      RECT 62.660000 0.000000 71.840000 332.800000 ;
      RECT 61.160000 0.000000 61.340000 332.800000 ;
      RECT 50.660000 0.000000 59.840000 332.800000 ;
      RECT 49.160000 0.000000 49.340000 332.800000 ;
      RECT 38.660000 0.000000 47.840000 332.800000 ;
      RECT 37.160000 0.000000 37.340000 332.800000 ;
      RECT 26.660000 0.000000 35.840000 332.800000 ;
      RECT 25.160000 0.000000 25.340000 332.800000 ;
      RECT 14.660000 0.000000 23.840000 332.800000 ;
      RECT 13.160000 0.000000 13.340000 332.800000 ;
      RECT 3.610000 0.000000 11.840000 332.800000 ;
      RECT 2.110000 0.000000 2.290000 332.800000 ;
      RECT 0.000000 0.000000 0.790000 332.800000 ;
  END
END oadm_dm

END LIBRARY
